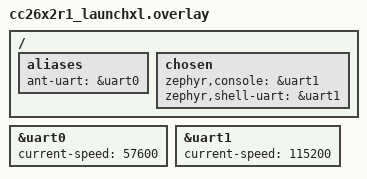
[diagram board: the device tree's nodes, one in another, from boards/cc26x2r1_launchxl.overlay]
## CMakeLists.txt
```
# SPDX-License-Identifier: Apache-2.0

cmake_minimum_required(VERSION 3.20.0)

# ANT+ dongle on the second vendor's silicon - a CC13x2/CC26x2 LaunchXL. See
# boards/cc26x2r1_launchxl.conf for what this board can and cannot do (no USB
# device peripheral at all, so the ANT serial protocol goes out a UART).
#
# UNVERIFIED PENDING HARDWARE beyond a single bring-up bench: the coexistence
# arm (ti_coex.conf, CONFIG_RADIANT_COEX154_CC26XX_FORK) builds but has never
# run against a real 802.15.4 peer. See radiant/coex154_ti/ and
# ti_coex.conf's own header before recording anything off that arm. This is
# recorded in the README, not just here.
#
# The sysbuild-cache reader and the RADIANT_BACKEND selection/assertion
# machinery are shared with every other RadiANT app (apps/dongle,
# apps/dongle_thread, apps/hrm_ble) - see cmake/radiant_backend.cmake for the
# sysbuild mechanics this depends on. The ANT_RADIO axis lives in
# apps/common/ instead, same reason as every other ANT-serial application.
include("${CMAKE_CURRENT_SOURCE_DIR}/../../cmake/radiant_backend.cmake")
include("${CMAKE_CURRENT_SOURCE_DIR}/../common/ant_radio_backend.cmake")

# THE DEFAULT IS "cc26xx" - the only backend that means anything on this
# silicon. RADIANT_BACKEND_NRF names a TIMER this part does not have and could
# never configure here, so cc26xx is not merely the useful default, it is the
# only real one.
#
# It used to be "null", to keep a bare `west build apps/dongle_ti` configuring
# and linking with no -DEXTRA_ZEPHYR_MODULES and no hal_ti checkout. That
# property is exactly what is being given up, and deliberately: what it bought
# was a build that succeeds while producing an image whose radio refuses every
# arm. A bare build that now fails for want of hal_ti says so immediately;
# a bare build that used to succeed said nothing, and the resulting image is
# indistinguishable from a dead antenna until somebody spends a bench session
# on it.
#
# Every real build of this application already passes -DRADIANT_BACKEND=cc26xx
# explicitly (see scripts/build_all.ps1's TI rows and scripts/flash_ti.ps1),
# so this changes no build anybody runs - and the .config read-back after the
# build is still what actually proves which backend was compiled, see
# radiant_assert_backend() below.
radiant_select_backend("${CMAKE_CURRENT_SOURCE_DIR}/../../radiant" "cc26xx" RADIANT_BACKEND_CONF)
ant_select_radio("${CMAKE_CURRENT_SOURCE_DIR}" "" "${RADIANT_BACKEND_CONF}" ANT_RADIO_CONF)

# Write only on a change - see apps/dongle/CMakeLists.txt for the full
# rationale.
set(ANT_RADIO_CONF_FILE "${CMAKE_CURRENT_BINARY_DIR}/ant_radio_backend.conf")
set(ANT_RADIO_CONF_EXISTING "")
if(EXISTS "${ANT_RADIO_CONF_FILE}")
  file(READ "${ANT_RADIO_CONF_FILE}" ANT_RADIO_CONF_EXISTING)
endif()
if(NOT ANT_RADIO_CONF_EXISTING STREQUAL ANT_RADIO_CONF)
  file(WRITE "${ANT_RADIO_CONF_FILE}" "# Generated by CMakeLists.txt from -DANT_RADIO. Do not edit; do not commit.\n${ANT_RADIO_CONF}")
endif()

find_package(Zephyr REQUIRED HINTS $ENV{ZEPHYR_BASE})
project(radiant_dongle_ti)

ant_assert_radio("radiant_dongle_ti")

target_sources(app PRIVATE src/main.c)

# ── apps/common: the antr_* seam, the serial bridge and its transports ─────
#
# Same file, same reasoning as apps/dongle and apps/dongle_thread. This board
# always lands on CONFIG_ANT_DONGLE_TRANSPORT_UART (see boards/*.conf - there
# is no USB device peripheral on this part at all), so only
# apps/common/ant_uart_transport.c actually compiles out of the transport
# trio.
include("${CMAKE_CURRENT_SOURCE_DIR}/../common/sources.cmake")

# ── The hostless node's identity (compat-C6) ────────────────────────────────
#
# Same wiring as apps/dongle's and apps/dongle_thread's own CMakeLists.txt.
# Off by default here too.
if(CONFIG_RADIANT_NODE_IDENT)
  target_sources(app PRIVATE ../../radiant/src/node/node_ident.c)
  target_include_directories(app PRIVATE ../../radiant/src/node)
endif()
if(CONFIG_RADIANT_NODE_NVM_SETTINGS)
  target_sources(app PRIVATE ../../radiant/src/node/node_nvm_settings.c)
endif()
```

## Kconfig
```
# ANT+ USB Dongle, TI CC26x2 port — application configuration
#
# UNVERIFIED PENDING HARDWARE beyond a single bring-up bench - see this
# application's own CMakeLists.txt header and README.md.

menu "ANT+ Dongle (TI CC26x2)"

choice ANT_DONGLE_TRANSPORT
	prompt "Transport carrying the ANT serial protocol"
	default ANT_DONGLE_TRANSPORT_UART
	help
	  UART is the only transport here: the CC13x2/CC26x2 has no USB device
	  peripheral, so apps/common/ant_uart_transport.c is the one compiled.
	  The symbol name matches apps/dongle's, so apps/common/sources.cmake
	  selects it the same way. See apps/common/ant_transport.h for the
	  common interface.

config ANT_DONGLE_TRANSPORT_UART
	bool "Plain UART"
	help
	  The CP2102N-based module this board's UART stands in for is a
	  Dynastream ANT2USB - a UART-to-USB bridge in a plastic shell, which is
	  what a "USB ANT stick" always was underneath. See
	  boards/cc26x2r1_launchxl.overlay for which UART carries ANT and which
	  carries the log, and why they are never the same one.

endchoice

config UART_INTERRUPT_DRIVEN
	default y if ANT_DONGLE_TRANSPORT_UART

config ANT_DONGLE_UART_BAUD
	int "Baud rate of the UART carrying the ANT serial protocol"
	depends on ANT_DONGLE_TRANSPORT_UART
	default 57600 if SOC_SERIES_CC13X2_CC26X2
	default 115200
	help
	  57600 on this part, and that is not a typo - see
	  boards/cc26x2r1_launchxl.overlay's own header for the full story: the
	  deployment target is a CC2652P + CP2102N module impersonating a real
	  Dynastream ANT2USB, and a real ANT2USB is a 57600 device. This symbol
	  RECORDS the rate; apps/common/ant_uart_transport.c BUILD_ASSERTs that
	  it agrees with the devicetree's current-speed, so the two cannot
	  silently drift apart.

# CONFIG_RADIANT_ANTR_API and CONFIG_RADIANT_SEC_HOST_MESSAGES: the
# antr_* adapter's own symbols, shared with every other ANT-serial
# application. See apps/common/Kconfig.antr_api's own header.
rsource "../common/Kconfig.antr_api"

# CONFIG_ANT_DONGLE_ACTIVITY_COUNT and _CLAIMED: the shared receive-activity
# counter and its one-reader interlock. See that file's own header.
rsource "../common/Kconfig.activity"

# CONFIG_ANT_DONGLE_HEARTBEAT_LED and friends: the mono led0 flash and its
# off-switch. This application does NOT rsource Kconfig.dongle_main - it has
# its own hand-written main() - but it ends that main() with the same
# ant_heartbeat_led_run() call, so it needs these symbols and not those.
#
# boards/ti/cc2652p_dongle defines led0 on DIO6. No LaunchXL variant in this
# tree defines one, and there the shared file compiles down to a thread that
# sleeps.
rsource "../common/Kconfig.heartbeat_led"

# CONFIG_ANT_DONGLE_HEALTH_COUNTERS: the 0xF6 health counters, off by default
# (see that file's own header). Sourced so ti_health.conf can turn them on: on
# a LaunchXL whose log UART has nothing attached, 0xF6 over the ANT UART is
# the one way to read SCHED_DENIED off a running image.
rsource "../common/Kconfig.health"

choice ANT_DONGLE_RADIO
	prompt "ANT radio backend"
	default ANT_DONGLE_RADIO_CORE
	help
	  Which implementation of radiant/include/radiant/ant_radio.h is compiled.

	  UNLIKE EVERY OTHER APPLICATION IN THIS REPOSITORY, "sdk_ant" is not a
	  real option here: sdk-ant is Nordic's proprietary radio stack, built
	  against Nordic silicon, and this board's radio is TI's RF core. The
	  option still exists so the choice has the same shape as the other
	  applications' copies of it; selecting it here
	  produces a build with no radiant module and no sdk-ant module either,
	  which fails at the antr_* link rather than doing anything useful.

	  As with every other application, this choice does not actually decide
	  anything - see apps/dongle/Kconfig's copy of this same note for why
	  CMake's ANT_RADIO cache variable is the real switch and this choice
	  only mirrors its result into .config.

config ANT_DONGLE_RADIO_SDK_ANT
	bool "Nordic's prebuilt ANT stack (sdk-ant) - NOT SUPPORTED ON THIS BOARD"

config ANT_DONGLE_RADIO_CORE
	bool "radiant, the clean-room stack"
	help
	  Compile radiant/ with CONFIG_RADIANT_BACKEND_CC26XX=y, the only
	  radiant HAL backend this silicon has. See
	  radiant/src/radiant_radio_cc26xx.c and docs/decisions/0014 and 0015
	  for the port itself; UNVERIFIED PENDING HARDWARE beyond a single
	  bring-up bench for the coexistence arm - see this application's own
	  CMakeLists.txt header.

config ANT_DONGLE_RADIO_STUB
	bool "Stub out the ANT radio layer"
	help
	  Compile apps/common/ant_radio_stub.c. Useful for bringing up the UART
	  bridge and the rest of the board without a working radio at all - the
	  cheapest proof the antr_* seam holds on a new SoC.

endchoice

config ANT_DONGLE_UF2_SETTLE_MS
	int "Settling delay after a soft reset, before USB comes up (ms)"
	default 0
	range 0 5000
	help
	  This board has no UF2 bootloader - see boards/cc26x2r1_launchxl.conf
	  - so the race this delay exists for cannot happen here. Left at 0
	  rather than removed, so this application's Kconfig tree keeps the same
	  shape as apps/dongle's and apps/dongle_thread's.

config ANT_DONGLE_TX_POWER_BOOST
	bool "Transmit at the radio's maximum power by default"
	default y
	help
	  See apps/dongle/Kconfig's own copy of this symbol. On the TI backend
	  the boosted LVL_5 (+8 dBm) is rounded down to the highest table entry
	  not above it (radiant/src/radiant_radio_cc26xx.c), which is +5 dBm;
	  before 2026-11 the boost asked for LVL_4 here and got +4.

endmenu

# The hostless node's identity and epoch (compat-C6), and the compatibility
# profiles' policy settings (compat-C7). Same wiring as apps/dongle/Kconfig
# and apps/dongle_thread/Kconfig - see those files' own comments.
rsource "../../radiant/src/node/Kconfig"
rsource "../../radiant/src/profiles/Kconfig"

source "Kconfig.zephyr"
```

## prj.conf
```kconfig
# Board-specific settings live in boards/cc26x2r1_launchxl.conf: which UART
# carries ANT and which carries the log, RTT off (no J-Link on this probe),
# immediate logging so a fault message survives a stack overflow, and thread
# naming so a fault dump names the thread that overflowed.

# The ANT stack settings are written by CMakeLists.txt into a generated
# fragment alongside the CONFIG_ANT_DONGLE_RADIO_* symbol naming the backend,
# same as every other RadiANT application - they name symbols that exist only
# once CMake has decided which Kconfig tree (sdk-ant's, or none) gets sourced.

CONFIG_LOG=y
CONFIG_LOG_MODE_DEFERRED=y

# Heap and threads
CONFIG_HEAP_MEM_POOL_SIZE=4096
CONFIG_MAIN_STACK_SIZE=2048
CONFIG_RESET_ON_FATAL_ERROR=y
CONFIG_REBOOT=y

CONFIG_SHELL=n

# Ring buffer for the serial bridge's RX path
CONFIG_RING_BUFFER=y

# The boot reset cause - see apps/dongle/prj.conf. On this dongle it is what
# the boot STARTUP reports to a host whose CP2102N handle survived the reboot.
CONFIG_HWINFO=y
```

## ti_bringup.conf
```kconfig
# Bring-up fragment for a TI board with no console but a debugger.
#
# WHAT THIS IS FOR, precisely. prj.conf sets CONFIG_RESET_ON_FATAL_ERROR=y,
# which is right for a shipped dongle and actively hostile during first
# bring-up on a board whose only console is a RAM buffer:
#
#   * The reset re-zeroes BSS, and the RTT control block lives in BSS. So the
#     fault message that CONFIG_LOG_MODE_IMMEDIATE just wrote is erased by the
#     reset that the fault caused, and scripts/ti/rtt_dump.ps1 reports an
#     uninitialised control block - which reads as "the image never started".
#   * A board resetting every few milliseconds cannot be halted. The ICEPick
#     still scans, so `dslite --list-cores` succeeds and the probe looks
#     healthy, while every DSS halt returns "Unable to access the DAP ... try
#     more reliable JTAG settings", twenty times over. That message points at
#     the probe, the wiring and the clock speed. It is none of those.
#
# Together those two produce a board that is loudly failing and presents as a
# board that is silently dead, with the diagnostic pointing at the debug rig.
# This fragment breaks that: a fault parks the core in the fatal handler, where
# the DAP answers, the RTT buffer still holds the dump, and
# scripts/ti/dss_alive.js can read CFSR/HFSR off a core that stayed put.
#
#   west build ... -- -DEXTRA_CONF_FILE=ti_bringup.conf
#   .\scripts\ti\rtt_dump.ps1
#
# NOT for anything that gets flashed and left. A dongle that hangs forever on a
# transient fault is worse than one that reboots.
CONFIG_RESET_ON_FATAL_ERROR=n

# Immediate logging, so a fault dump is written before the system dies rather
# than queued for a log thread that may no longer run. The LaunchXL's board
# file no longer sets it by default: on a running radio it stalls the ANT UART
# and misses ACK replies (see boards/cc26x2r1_launchxl.conf). Bring-up only.
CONFIG_LOG_MODE_IMMEDIATE=y

# Say something unconditionally, at the earliest point Zephyr can. Every log
# line in this application comes from main() or later, so an image that dies in
# a PRE_KERNEL driver init produces an empty buffer that is indistinguishable
# from an image that never ran at all - the exact ambiguity this fragment
# exists to remove. The banner is printed by the kernel before main() and costs
# a few hundred bytes.
CONFIG_BOOT_BANNER=y
CONFIG_EARLY_CONSOLE=y

# Put the LED back to the loud 1 Hz square wave the shipping image no longer
# uses. The shipping pattern is 30 ms every 4 s, which is right for a dongle
# living on a desk and wrong for the job this fragment exists for: DIO6 was
# identified as an LED BY EYE off exactly this blink, and DIO7 is still only an
# inference (see boards/ti/cc2652p_dongle/cc2652p_dongle.dts). Watching for a
# 30 ms flash on an unknown pin, once every four seconds, is not a pin hunt -
# it is a staring contest.
#
# Also pins it to the fixed pattern: during bring-up the LED must mean "the
# main thread is alive" and nothing else, or a slow blink is ambiguous between
# a healthy idle radio and a wedged one.
CONFIG_ANT_DONGLE_HEARTBEAT_LED_ON_MS=500
CONFIG_ANT_DONGLE_HEARTBEAT_LED_OFF_MS=500
CONFIG_ANT_DONGLE_HEARTBEAT_LED_ACTIVITY=n
```

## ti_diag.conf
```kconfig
# SPDX-License-Identifier: Apache-2.0
#
# The 0xF7 diagnostic pages (MESG_RADIANT_DIAG, ADR 0023) on the TI dongle.
# Needs the 0xF6 health counters too, so stack it after ti_health.conf:
#
#   west ... -- "-DANT_RADIO=core" "-DRADIANT_BACKEND=cc26xx" \
#               "-DEXTRA_ZEPHYR_MODULES=<hal_ti path>" \
#               "-DEXTRA_CONF_FILE=ti_health.conf;ti_diag.conf"
#
# Read with tools/ant_diag.py --port COM11 --baud 57600. A bench build: the
# counters cost a few increments on the radio paths and nothing on the wire
# unless asked.
#
# CHECK THE GENERATED .config: CONFIG_ANT_DONGLE_DIAG=y and
# CONFIG_RADIANT_DIAG_COUNTERS=y.
CONFIG_ANT_DONGLE_DIAG=y
```

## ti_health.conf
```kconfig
# SPDX-License-Identifier: Apache-2.0
#
# Enable the 0xF6 health counters (MESG_RADIANT_HEALTH) on the TI dongle.
# Stacks on top of an arm fragment:
#
#   west ... -- "-DANT_RADIO=core" "-DRADIANT_BACKEND=cc26xx" \
#               "-DEXTRA_ZEPHYR_MODULES=<hal_ti path>" \
#               "-DEXTRA_CONF_FILE=ti_gate.conf;ti_health.conf"
#
# Read with tools/ant_health.py over the ANT UART. ANT_HEALTH_SCHED_DENIED is
# where an arm refused by RF_scheduleCmd() lands (synchronous EDENIED ->
# radiant_sched.c arm_failed() -> notify_done(DENIED)).
#
# CHECK THE GENERATED .config: CONFIG_ANT_DONGLE_HEALTH_COUNTERS=y, plus the
# arm fragment's own symbols - a semicolon list that lost its second half
# builds cleanly without either.
CONFIG_ANT_DONGLE_HEALTH_COUNTERS=y
```

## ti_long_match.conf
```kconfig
# SPDX-License-Identifier: Apache-2.0
#
# The A image of a cc26xx wildcard-search A/B (ADR 0022 on TI): the 24-bit
# hardware match, [A6 C5 devnum_lo], and the 128-set sweep (~33 s per pass).
# CONFIG_RADIANT_SEARCH_SHORT_MATCH defaults to y on cc26xx since 2026-11-12;
# this fragment turns it back off for comparison.
#
#   west ... -- "-DANT_RADIO=core" "-DRADIANT_BACKEND=cc26xx" \
#               "-DEXTRA_ZEPHYR_MODULES=<hal_ti path>" \
#               "-DEXTRA_CONF_FILE=ti_long_match.conf"
#
# A fragment rather than a bare -D on the command line, which may not reach
# the image under sysbuild. On this radio the setting changes EVERY hardware
# match, tracking windows too (formatConf.nSwBits is fixed per RF_open()).
#
# Check the generated .config, not the build log:
#
#   Select-String build\<dir>\dongle_ti\zephyr\.config -Pattern "SHORT_MATCH|BACKEND_CC26XX="
#
# Expect CONFIG_RADIANT_BACKEND_CC26XX=y and the short match "is not set".

CONFIG_RADIANT_SEARCH_SHORT_MATCH=n
```

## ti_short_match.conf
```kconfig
# SPDX-License-Identifier: Apache-2.0
#
# The B image of the cc26xx wildcard-search A/B (ADR 0022 on TI): the search
# matches [A6 C5] in hardware and takes devnum_lo from the first payload byte,
# so the sweep is ONE set instead of 128 (~33 s per pass).
#
#   west ... -- "-DANT_RADIO=core" "-DRADIANT_BACKEND=cc26xx" \
#               "-DEXTRA_ZEPHYR_MODULES=<hal_ti path>" \
#               "-DEXTRA_CONF_FILE=ti_short_match.conf"
#
# A fragment rather than a bare -DCONFIG_RADIANT_SEARCH_SHORT_MATCH=y on the
# command line, which may not reach the image under sysbuild.
#
# ON THIS RADIO IT SHORTENS EVERY HARDWARE MATCH, TRACKING TOO.
# formatConf.nSwBits is fixed per RF_open(), so the sync word is 16 bits for
# every window, and a tracking window compares three address bytes in software
# (two in the A image). That is the cost the A/B measures: read
# radiant_cc26xx_sw_addr_mismatch / radiant_cc26xx_sync_frames over JTAG (by
# address from arm-zephyr-eabi-nm on the ELF) in both images.
#
# CHECK THE GENERATED .config, NOT THE BUILD LOG:
#
#   Select-String build\<dir>\dongle_ti\zephyr\.config -Pattern "SHORT_MATCH|BACKEND_CC26XX="
#
# Expect CONFIG_RADIANT_BACKEND_CC26XX=y and CONFIG_RADIANT_SEARCH_SHORT_MATCH=y.

CONFIG_RADIANT_SEARCH_SHORT_MATCH=y
```

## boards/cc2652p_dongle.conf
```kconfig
# CC2652P + CP2102N USB dongle - the deployment target apps/dongle_ti was
# always written for. The LaunchXL arm exists to prove the port on a board with
# a debugger, a backchannel UART and LEDs whose positions are documented; this
# is the sealed stick it stands in for.
#
#   . .\scripts\env.ps1 -NcsVersion v3.4.0
#   .\scripts\fetch_hal_ti.ps1                 (once - NCS filters hal_ti out)
#   west build -s apps/dongle_ti -b cc2652p_dongle -- `
#       -DBOARD_ROOT=<repo> -DANT_RADIO=core -DRADIANT_BACKEND=cc26xx `
#       -DEXTRA_ZEPHYR_MODULES=C:/ncs/v3.4.0/modules/hal/ti
#
# Flash with scripts\flash_ti.ps1 -Ccxml scripts\ti\cc2652p_dongle.ccxml.
# THERE IS NO OTHER WAY IN. The ROM serial bootloader listens on DIO2/DIO3,
# fixed in silicon, and this module's bridge is on DIO12/DIO13 - so the JTAG
# rig is not the convenient route, it is the only route. See the board's
# devicetree header.

CONFIG_ANT_DONGLE_TRANSPORT_UART=y

# ── The log goes to RTT, because there is nowhere else for it to go ─────────
#
# THIS IS THE ONE PLACE THIS BOARD DIFFERS FROM THE LAUNCHXL IN KIND rather
# than in pin numbers, so it is worth being explicit.
#
# The LaunchXL's rule is "uart0 carries ANT, uart1 carries the log", and its
# .conf turns RTT OFF on the grounds that SEGGER's RTT needs a J-Link and this
# bench's TI probe is an XDS110. That reasoning is half right and the half that
# is wrong matters here: RTT is nothing but a ring buffer in RAM with a
# findable signature. A J-Link is needed to read it WITH SEGGER'S OWN TOOLS -
# it is not needed to read RAM. The XDS110 reads RAM perfectly well through
# DebugServer Scripting, which is how this board's part number, CCFG and entire
# pin map were recovered in the first place.
#
# And on this board there is no alternative to weigh it against. uart1's pins
# are inside a sealed USB shell, so a log on uart1 is a log nobody can ever
# read; a log on uart0 corrupts the ANT stream, which is the exact failure the
# LaunchXL's separation exists to prevent. RTT is the only port left.
#
# Read it with scripts\ti\rtt_dump.ps1, which needs no USB connection to the
# dongle at all - only the XDS110 wiring that flashed it. That property is why
# bring-up on this board is not blind.
CONFIG_SERIAL=y
CONFIG_USE_SEGGER_RTT=y
CONFIG_LOG_BACKEND_RTT=y
CONFIG_RTT_CONSOLE=y

# Console OFF the UART, hard. uart0 is the ANT stream and the overlay beside
# this file deletes the chosen console property to match; this is the symbol
# that actually stops the console driver binding to a UART.
CONFIG_CONSOLE=y
CONFIG_UART_CONSOLE=n
CONFIG_LOG_BACKEND_UART=n

# Immediate logging, for the same reason the LaunchXL arm sets it and with more
# force here: deferred logging turns a stack overflow into a board that simply
# goes quiet, because the fault message needs a log thread that no longer
# exists. That has already cost this project a session on the MPSL gate. This
# is a first bring-up on a board with no console at all unless a debugger is
# attached, which is precisely where an unexplained silence is most expensive.
CONFIG_LOG_MODE_IMMEDIATE=y

# Name the threads. On the first window the cc26xx backend ever ran, the
# LaunchXL reset inside the completion path and the dump said
# "Current thread: 0x200025e8 (unknown)" - and "(unknown)" cost an hour of
# guessing at three plausible stacks, none of which was the one. See
# boards/cc26x2r1_launchxl.conf for the whole story.
CONFIG_THREAD_NAME=y
```

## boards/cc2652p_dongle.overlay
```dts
/*
 * CC2652P + CP2102N USB dongle - which port carries ANT, and at what rate.
 *
 * ONE UART, AND IT IS SPOKEN FOR. Unlike the LaunchXL (see
 * cc26x2r1_launchxl.overlay), this board has exactly one wired serial port:
 * uart0 on DIO12/DIO13, into the CP2102N, out of the USB plug. That is the ANT
 * wire protocol and nothing else may appear in it - a host tool reading the
 * ANT stream would parse a log line as a frame and the resulting checksum
 * failures look like a radio problem.
 *
 * So the log does NOT go to a UART on this board. It goes to RTT, which the
 * board's .conf explains; uart1's pins are not brought out of the shell.
 *
 * 57600, NOT 115200, and this is the board the rule was written for. A real
 * Dynastream ANT2USB is a 57600 device, and the whole point of this dongle is
 * to be a drop-in for one - so tools/ant_probe.py and everything else here
 * needs `--baud 57600` explicitly, because SerialDevice defaults to 115200 and
 * forgetting it produces framing garbage that reads as "no response to reset",
 * indistinguishable from a hung image.
 *
 * CONFIG_ANT_DONGLE_UART_BAUD records the same number and
 * apps/common/ant_uart_transport.c BUILD_ASSERTs that the two agree, so this
 * property and that symbol cannot drift apart silently.
 *
 * NO radiant,radio-timer NODE, same as the LaunchXL and for the same reason:
 * TI's RF core carries its own timebase (the RAT) and takes absolute start
 * times directly, so there is no peripheral to name.
 */

/ {
	aliases {
		ant-uart = &uart0;
	};

	chosen {
		/*
		 * Deliberately NOT &uart0. The board's own devicetree points
		 * the console there because that is the only sane default for
		 * a board with one port; this application takes that port for
		 * ANT and moves the console off UARTs entirely (see the .conf
		 * beside this file). Leaving zephyr,console on uart0 while
		 * CONFIG_UART_CONSOLE=n would be harmless today and a trap the
		 * first time somebody turns UART_CONSOLE back on to debug
		 * something.
		 */
		/delete-property/ zephyr,console;
		/delete-property/ zephyr,shell-uart;
	};
};

&uart0 {
	status = "okay";
	current-speed = <57600>;
};
```

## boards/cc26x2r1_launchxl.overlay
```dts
/*
 * LAUNCHXL-CC26X2R1 - which UART carries ANT, which carries the log, and at
 * what rate.
 *
 * WHICH IS WHICH, AND WHY ROUND THIS WAY. uart0 is DIO12/DIO13, which on this
 * LaunchXL is the XDS110 backchannel: the same USB cable that programs the
 * board presents it to the host as a COM port (COM14 on this bench), with no
 * extra hardware. uart1 is DIO22/DIO24, brought out on BoosterPack header pins
 * 5 and 6 and connected to nothing.
 *
 * So ANT takes uart0 - it is the port a host tool can actually reach - and the
 * log takes uart1, where it needs a 3V3 USB-serial adapter clipped on to be
 * read at all. That is the right way round even though it makes bring-up
 * blind, because the ANT stream is what is under test and the whole point of
 * separating them is that nothing else may appear in it. Sharing one UART
 * between logs and ANT frames guarantees an afternoon lost to a host tool
 * parsing a log line as a frame.
 *
 * THE BAUD IS 57600 AND THAT IS NOT A TYPO. Every other board in this
 * repository runs its ANT UART at 115200, and tools/ant_probe.py's
 * SerialDevice defaults to it, so `--baud 57600` has to be passed explicitly
 * here and forgetting it produces framing garbage that reads as "no response
 * to reset" - indistinguishable from a hung image. The reason to take that
 * risk: the deployment target is a CC2652P + CP2102N module impersonating a
 * Dynastream ANT2USB (0FCF:1004), and a real ANT2USB is a 57600 device. A
 * LaunchXL that runs at a different rate from the dongle it stands in for is a
 * LaunchXL that proves slightly less than it appears to.
 *
 * CONFIG_ANT_DONGLE_UART_BAUD records the same number, and
 * src/ant_uart_transport.c BUILD_ASSERTs that the two agree - so this property
 * and that symbol cannot drift apart silently. See that assert for why the
 * failure it catches is worth a line of code.
 *
 * NO radiant,radio-timer NODE, unlike every nRF board here. That chosen node
 * names the TIMER the nrf backend captures t_sync into and schedules window
 * edges with. TI's RF core has its own timebase (the RAT) inside the core and
 * takes absolute start times directly, so there is no peripheral to name and
 * nothing for a second driver to collide with.
 */

/ {
	aliases {
		ant-uart = &uart0;
	};

	chosen {
		zephyr,console = &uart1;
		zephyr,shell-uart = &uart1;
	};
};

&uart0 {
	status = "okay";
	current-speed = <57600>;
};

&uart1 {
	status = "okay";
	current-speed = <115200>;
};
```

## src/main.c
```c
/* SPDX-License-Identifier: Apache-2.0 */

/*
 * ANT+ Dongle, TI CC26x2 port — main entry point.
 *
 * Same shape as apps/dongle/src/main.c, minus the UF2-bootloader settle. All
 * protocol work happens in the ANT bridge thread (apps/common/
 * ant_serial_bridge.c) and in antr_on_message(), which the bridge implements
 * and the radio backend calls.
 *
 * The LED heartbeat used to be a second copy of the loop in
 * apps/common/ant_dongle_main.c and is now the same shared call that file
 * makes - see apps/common/ant_heartbeat_led.h for why. The board-specific
 * alias assumption it used to carry is unchanged in substance: the shared file
 * is still guarded on `led0`, which boards/ti/cc2652p_dongle defines (DIO6) and
 * no LaunchXL variant in this tree does.
 *
 * UNVERIFIED PENDING HARDWARE beyond a single bring-up bench - see this
 * application's own CMakeLists.txt header and README.md.
 */

#include <zephyr/kernel.h>
#include <zephyr/logging/log.h>

#include "ant_heartbeat_led.h"
#include "ant_reset_cause.h"
#include "ant_serial_bridge.h"
#include "ant_transport.h"

/* The radio contract - whichever backend is compiled in behind it. Bringing
 * the stack up is the only thing main() needs from it.
 */
#include "ant_radio.h"

LOG_MODULE_REGISTER(ant_dongle_ti, LOG_LEVEL_INF);

int main(void)
{
	int ret;
	uint32_t cause;

	/* Read and cleared first, cached for the bridge's boot STARTUP - see
	 * apps/common/ant_reset_cause.h. Logged on every boot, so a dongle that
	 * rebooted itself mid-ride can be told from one that was replugged. */
	if (ant_reset_cause(&cause)) {
		LOG_INF("reset cause 0x%08x", cause);
	} else {
		LOG_INF("reset cause unknown (no hwinfo)");
	}

	LOG_INF("ANT+ Dongle (TI CC26x2) starting");

	ret = antr_init();
	if (ret) {
		LOG_ERR("antr_init failed: %d", ret);
		return ret;
	}
	LOG_INF("antr_init ok");

	/* Allocate the transport's buffers and start its writer thread, BEFORE
	 * the bridge exists to use them and before the UART is opened.
	 *
	 * Omitting this call was this port's longest-standing bug and it is
	 * worth being explicit about why it was invisible: the two ring buffers
	 * live in BSS, so a missing ring_buf_init() leaves them valid-looking
	 * objects of size ZERO rather than null pointers. Nothing crashes.
	 * ring_buf_put() simply accepts no bytes, so every byte the host sends
	 * is counted as dropped, and every byte the firmware sends waits a
	 * second for space that can never appear and is abandoned. The board
	 * boots, logs "transport up", blinks its LED, and is deaf and mute.
	 *
	 * apps/common/ant_dongle_main.c has always called this; this file is a
	 * hand-written main() for a board that file does not fit, and it is
	 * exactly the kind of thing a hand-written copy loses. ant_transport_
	 * enable() now refuses to open a UART whose buffers are unallocated, so
	 * this cannot fail silently again.
	 */
	usb_ant_class_init();
	LOG_INF("usb_ant_class_init ok");

	/* The bridge owns ANT event forwarding: it defines antr_on_message(),
	 * which the radio backend calls. Nothing is registered.
	 */
	ret = ant_serial_bridge_init();
	if (ret) {
		LOG_ERR("ant_serial_bridge_init failed: %d", ret);
		return ret;
	}
	LOG_INF("ant_serial_bridge_init ok");

	/* This board's only transport - see boards/cc26x2r1_launchxl.conf.
	 * Opens the UART carrying the ANT serial protocol.
	 */
	LOG_INF("enabling transport");
	ret = ant_transport_enable();
	if (ret) {
		LOG_ERR("ant_transport_enable failed: %d", ret);
		return ret;
	}
	LOG_INF("transport up");

	/* After the transport, never before (a UART write before it is
	 * refused). This is the board where it matters most: the CP2102N keeps
	 * the host's USB handle open across an MCU reboot, so without this the
	 * host sees only silence. */
	ant_serial_bridge_announce_boot();

	/* The heartbeat owns the main thread from here; it never returns, and
	 * on a board with no led0 alias it sleeps. Bring-up wants a louder
	 * pattern than the shipping 30 ms / 4 s one - see ti_bringup.conf.
	 */
	ant_heartbeat_led_run();

	return 0;
}
```
